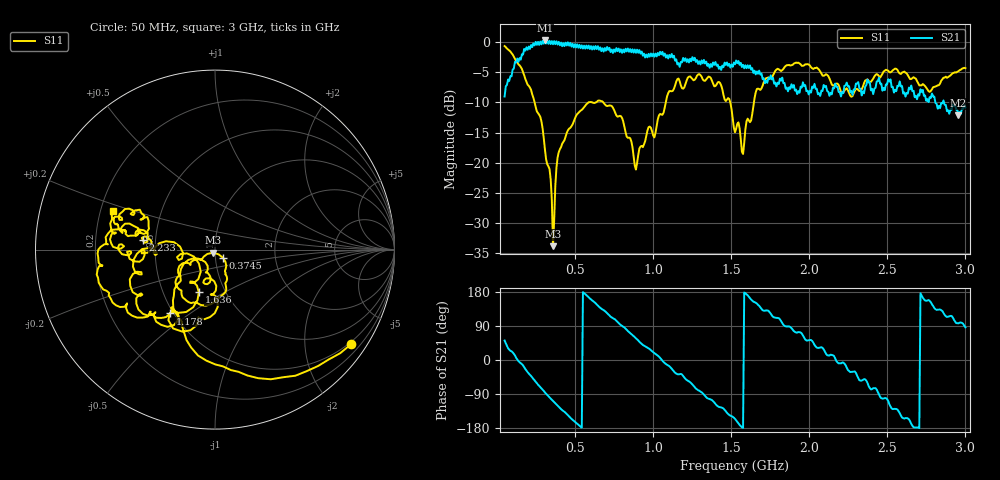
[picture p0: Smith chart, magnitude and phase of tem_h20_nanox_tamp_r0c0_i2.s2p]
! nanovna_capture.py 2026-10-26T21:51:19+0900
! NanoVNA-F_V2 fw 0.6.0 SN 4A3639384505514B
! cal: load open short thru cal'ed  over 50000000-3000000000 Hz, 201 points
! points 401, avg 4
! TEM h=20, tampered Nano X, 0 deg, centred, interleaved run T2
# HZ S RI R 50
! S12 and S22 are not measured (written as 0)
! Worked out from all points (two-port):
!   401 points, 50 MHz to 3 GHz, reference 50 ohm
!   highest |S21| = 0.24 dB at 308.1 MHz (marker M1); lowest = -12.2 dB at 2.956 GHz (marker M2)
!   |S21| within 3 dB of the highest: 130.9973 MHz to 131.2728 MHz (275.5 kHz wide, 0.21 % of centre); 154.7 MHz to 1.138 GHz (983.8 MHz wide, 152 % of centre) (the widest 2 of 7)
!   lowest |S11| = -33.8 dB at 359.8 MHz (marker M3), VSWR 1.04, Z = 48.9 - j1.7 ohm
!   |S11| at or under -10 dB: 242 MHz to 587.7 MHz (345.7 MHz wide, 83.3 % of centre); 681 MHz to 1.082 GHz (400.7 MHz wide, 45.5 % of centre); 1.495 GHz to 1.646 GHz (151.6 MHz wide, 9.65 % of centre) (the widest 3 of 4)
!   S12 and S22 are empty: the file has one direction only
!   S11 on the Smith chart (normalised r, x): 50 MHz: 0.44, -3.14; 374.5 MHz: 1.09, -0.10; 1.178 GHz: 0.48, -0.42; 1.636 GHz: 0.75, -0.38; 2.233 GHz: 0.42, +0.05; 3 GHz: 0.25, +0.17
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5e7  0.7586 -0.5267  0.221 0.2754  0 0  0 0
1.75375e8  -0.1585 -0.5046  0.8272 -0.282  0 0  0 0
3.08125e8  -0.1194 -0.0484  0.0826 -1.025  0 0  0 0
3.5975e8  -0.0108 -0.0173  -0.2947 -0.91  0 0  0 0
3.745e8  0.0447 -0.0457  -0.3923 -0.8736  0 0  0 0
4.04e8  0.0559 -0.1167  -0.5622 -0.7501  0 0  0 0
5.44125e8  0.0146 -0.2736  -0.9358 -0.0209  0 0  0 0
7.80125e8  -0.1934 -0.1457  -0.1117 0.8741  0 0  0 0
8.9075e8  -0.0542 -0.0692  0.4351 0.6869  0 0  0 0
1.03825e9  -0.00911 -0.2464  0.7667 0.1187  0 0  0 0
1.178375e9  -0.252 -0.356  0.5482 -0.4078  0 0  0 0
1.325875e9  -0.4115 -0.2439  -0.0158 -0.7092  0 0  0 0
1.525e9  -0.1777 -0.0194  -0.5918 -0.2728  0 0  0 0
1.576625e9  -0.0897 -0.0771  -0.646 -0.00773  0 0  0 0
1.635625e9  -0.0902 -0.2375  -0.5569 0.2403  0 0  0 0
1.783125e9  -0.4351 -0.3785  -0.1694 0.428  0 0  0 0
2.019125e9  -0.6041 0.031  0.2722 0.3289  0 0  0 0
2.233e9  -0.4029 0.0526  0.4242 -0.1019  0 0  0 0
2.51325e9  -0.5531 0.0948  -0.2115 -0.4194  0 0  0 0
2.712375e9  -0.3943 0.1881  -0.4045 0.0267  0 0  0 0
2.95575e9  -0.5553 0.1412  -0.029 0.2445  0 0  0 0
3e9  -0.5667 0.2145  0.0204 0.2859  0 0  0 0
